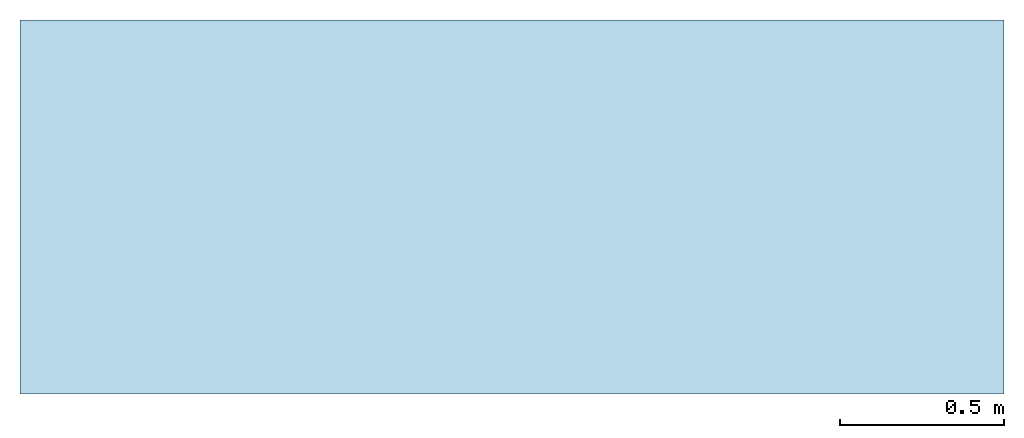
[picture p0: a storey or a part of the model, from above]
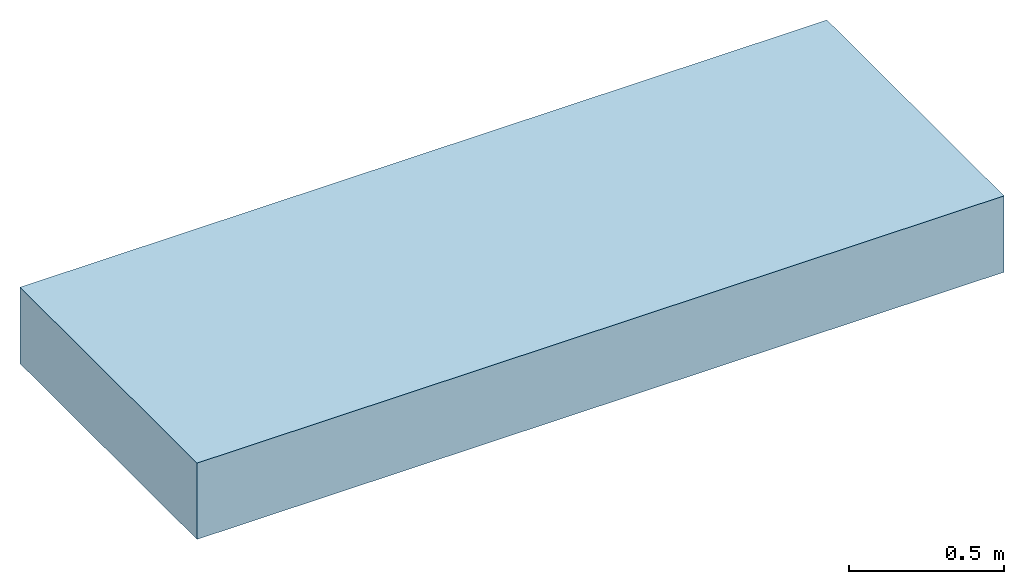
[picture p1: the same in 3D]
Properties of the parts of a building model (IFC2X3)

# File
Description: ViewDefinition [CoordinationView_V2.0, QuantityTakeOffAddOnView], RevitIdentifiers [ContentGUID: 704ee8e6-b7a5-4cdf-b516-c9cadaf13e75, VersionGUID: 389b4207-f0f3-4822-9464-d6dd4e263762, NumberOfSaves: 43], CoordinateReference [CoordinateBase: Shared Coordinates, ProjectSite: Internal]
File name: Solucion panel prefabricado ligero.ifc
Time: 2026-03-16T11:33:09+01:00
Written by: ODA SDAI 24.6
Made in: Autodesk Revit 24.3.40.26 (ESP) - IFC 24.3.20.0

# IfcProject, 000000
LongName: Solución panel prefabricado ligero de fachada

# IfcSite, Default
RefLatitude: 40, 25, 13, 9643; RefLongitude: -3, -42, -20, -772056; RefElevation: 0 m
Otra - Categoría: Información de proyecto; Dirección de proyecto: Parque Empresarial de A Pontenova , Parcelas 33-39 , 27720 · A Pontenova · (Lugo); Fecha de emisión de proyecto: 25-11-2025; Nombre de cliente: Recense; Nombre de proyecto: Solución panel prefabricado ligero de fachada; Número de proyecto: 000000
Datos de identidad - Autor: Deliprogal; Descripción de organización: Fijaciones a medida para prefabricado; Nombre de organización: Recense

# IfcBuilding
Pset_BuildingCommon - NumberOfStoreys: 3
Otra - Categoría: Información de proyecto; Dirección de proyecto: Parque Empresarial de A Pontenova , Parcelas 33-39 , 27720 · A Pontenova · (Lugo); Fecha de emisión de proyecto: 25-11-2025; Nombre de cliente: Recense; Nombre de proyecto: Solución panel prefabricado ligero de fachada; Número de proyecto: 000000
Datos de identidad - Autor: Deliprogal; Descripción de organización: Fijaciones a medida para prefabricado; Nombre de organización: Recense

# IfcBuildingStorey: Nivel:8mm Head (4)
Otra - Categoría: Niveles; Familia: Nivel; Familia y tipo: Nivel: 8mm Head; ID de tipo: 305; Tipo: 8mm Head
Cotas - Altura de cálculo: 0 m
Datos de identidad - Estructura: no; Planta de edificio: yes
Otra(Tipo) - Categoría: Niveles; Nombre de familia: Nivel
Restricciones(Tipo) - Base de elevación: Punto base del proyecto
Gráficos(Tipo) - Color: 12615680; Grosor de línea: 1; Patrón de línea: Dash dot; Símbolo en extremo 1 por defecto: no; Símbolo en extremo 2 por defecto: yes
Datos de identidad(Tipo) - Nombre de tipo: 8mm Head
Name | LongName = Nombre | Elevation (m) = Elevación (m)
B1 | B1 | -3
L0 | L0 | 0
L1 | L1 | 3
R1 | R1 | 6

# IfcBuildingElementProxy: Panel Hormigón:Panel Hormigón, Panel Hormigón:Panel Hormigón:3637775
In: B1
Type - Material: Hormigón reforzado con fibra de vidrio
Type - Otra - Categoría: Modelos genéricos; Nombre de familia: Panel Hormigón
Type - Restricciones - Elevación por defecto: 13.1234 m
Type - Datos de identidad - Nombre de tipo: Panel Hormigón
Pset_BuildingElementProxyCommon - Reference: Panel Hormigón; sets with these values: 2
Otra - Familia: Panel Hormigón; Familia y tipo: Panel Hormigón: Panel Hormigón; ID de tipo: 3674676; Tipo: Panel Hormigón
Restricciones - Desfase desde el anfitrión: -0.15 m; Elevación desde el nivel: 0 m; Plano de trabajo: <no asociado>
Cotas - Área: 9.7315 m2; Volumen: 1.0797 m3
Proceso por fases - Fase de creación: New

# IfcCovering: Techo compuesto:Aislamiento, Techo compuesto:Aislamiento:3635725
In: L0
Type - PredefinedType: CEILING
Type - Otra - Categoría: Techos; Nombre de familia: Techo compuesto
Type - Construcción - Grosor: 0.08 m
Type - Gráficos - Color de relleno de detalle bajo: 0
Type - Datos de identidad - Nombre de tipo: Aislamiento
Type - Propiedades analíticas - Absortancia: 0.7; Aspereza: 3; Coeficiente de transferencia de calor (U): 0.425 kg/K/s3; Masa térmica: 11360 kg/K/s2; Resistencia térmica (R): 2.35294 s3*K/kg
Type - Pset_CoveringCommon - TotalThickness: 0.08 m
Material: Lana de roca 0.08 m
Pset_CoveringCommon - Reference: Aislamiento; sets with these values: 2
BaseQuantities - GrossCeilingArea: 1.4356 m2
Otra - Familia: Techo compuesto; Familia y tipo: Techo compuesto: Aislamiento; ID de tipo: 3635518; Tipo: Aislamiento
Restricciones - Delimitación de habitación: yes; Nivel: L0; Desfase de altura desde nivel: 2.61 m
Cotas - Área: 1.4356 m2; Perímetro: 4.9 m; Volumen: 0.114848 m3
Proceso por fases - Fase de creación: New

# IfcCovering: Techo compuesto:Placa, Techo compuesto:Placa:3635732
In: L0
Type - PredefinedType: CEILING
Type - Otra - Categoría: Techos; Nombre de familia: Techo compuesto
Type - Construcción - Grosor: 0.01 m
Type - Gráficos - Color de relleno de detalle bajo: 0
Type - Datos de identidad - Nombre de tipo: Placa
Type - Propiedades analíticas - Absortancia: 0.7; Aspereza: 3; Coeficiente de transferencia de calor (U): 51 kg/K/s3; Masa térmica: 10752 kg/K/s2; Resistencia térmica (R): 0.0196078 s3*K/kg
Type - Pset_CoveringCommon - TotalThickness: 0.01 m
Material: Enlucido 0.01 m
Pset_CoveringCommon - Reference: Placa; Finish: Enlucido;
Pset_QuantityTakeOff - Reference: Placa
BaseQuantities - GrossCeilingArea: 1.2672 m2
Otra - Familia: Techo compuesto; Familia y tipo: Techo compuesto: Placa; ID de tipo: 3635581; Tipo: Placa
Restricciones - Delimitación de habitación: yes; Nivel: L0; Desfase de altura desde nivel: 2.6 m
Cotas - Área: 1.2672 m2; Perímetro: 4.56 m; Volumen: 0.012672 m3
Proceso por fases - Fase de creación: New

# IfcElementAssembly: GEN-A-M12:A-M12 (2)
In: L0
Type - Material: REC_Acero, S 275JR (Zincado)
Type - Otra - Categoría: Conexiones estructurales; Nombre de familia: GEN-A-M12
Type - Restricciones - Elevación por defecto: 0 m
Type - Datos - Classification.Uniclass.Pr.Description: Bolts and accessories; Classification.Uniclass.Pr.Number: Pr_20_29_08
Type - Datos de identidad - Código de montaje: Tornillo perfil hormigón M12x50 mm (8.8); Costo: 0; Creado por:: Deliprogal SL; Descripción: Arandela M12; Description_ESP: Concrete profile screw M12x50 mm (8.8); Fabricante: RECENSE; Fecha de Creacion:: 09/11/2025; Fecha Ultima Revision:: 12/02/2026; Keynote_ESP: Screw for fixing elements to the concrete profile PH4022; Modelo: TPH1250; Nombre de tipo: A-M12; Nota clave: Tornillo para fijar elementos al Perfil de Hormigón PH4022; URL: https://prefabricados.recense.com/prefabricados/fijacion/fijacion-antivuelco-hormigon/tph/
Classification: Tornillo perfil hormigón M12x50 mm (8.8) (Uniformat)
Pset_QuantityTakeOff - Reference: A-M12
Otra - Familia: GEN-A-M12; Familia y tipo: GEN-A-M12: A-M12; ID de tipo: 3651128; Tipo: A-M12
Restricciones - Se mueve con elementos cercanos: no; Anfitrión: Ninguno
Datos - DPG_FABRICA: IL; DPG_NUMERO_OT: OT-
Cotas - Área: 0.000441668 m2; Volumen: 7.16248e-07 m3
Proceso por fases - Fase de creación: New
Name (GEN-A-M12:A-M12:...)
3714486
3714490

# IfcElementAssembly: GEN-T-M12:T-M12 (2)
In: L0
Type - Material: REC_Acero, S 275JR (Zincado)
Type - Otra - Categoría: Conexiones estructurales; Nombre de familia: GEN-T-M12
Type - Restricciones - Elevación por defecto: 0 m
Type - Datos - Classification.Uniclass.Pr.Description: Bolts and accessories; Classification.Uniclass.Pr.Number: Pr_20_29_08
Type - Datos de identidad - Costo: 0; Creado por:: Deliprogal SL; Descripción: Concrete profile screw M12x50 mm (8.8); Description_ESP: Tornillo perfil hormigón M12x50 mm (8.8).; Fabricante: FERRETERÍA; Fecha de Creacion:: 01/03/2024; Fecha Ultima Revision:: 01/03/2024; Keynote_ESP: Screw for fixing elements to the concrete profile PH4022.; Modelo: TPH1250; Nombre de tipo: T-M12; Nota clave: Tornillo para fijar elementos al Perfil de Hormigón PH4022.; URL: https://prefabricados.recense.com/prefabricados/fijacion/fijacion-antivuelco-hormigon/tph/
Pset_QuantityTakeOff - Reference: T-M12
Otra - Familia: GEN-T-M12; Familia y tipo: GEN-T-M12: T-M12; ID de tipo: 3648613; Tipo: T-M12
Restricciones - Se mueve con elementos cercanos: no; Anfitrión: Ninguno
Cotas - Área: 0.000789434 m2; Volumen: 0.00000247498 m3
Proceso por fases - Fase de creación: New
Name (GEN-T-M12:T-M12:...)
3714487
3714491

# IfcElementAssembly: REC-A-M16:A-M16 (2)
In: L0
Type - Material: REC_Acero, S 275JR (Zincado)
Type - Otra - Categoría: Conexiones estructurales; Nombre de familia: REC-A-M16
Type - Restricciones - Elevación por defecto: 0 m
Type - Datos - Classification.Uniclass.Pr.Description: Bolts and accessories; Classification.Uniclass.Pr.Number: Pr_20_29_08
Type - Datos de identidad - Costo: 0; Creado por:: Deliprogal SL; Descripción: Arandela M16; Fabricante: RECENSE; Fecha de Creacion:: 01/03/2024; Fecha Ultima Revision:: 01/03/2024; Modelo: A-M16; Nombre de tipo: A-M16; URL: https://recense.com/
Pset_QuantityTakeOff - Reference: A-M16
Otra - Familia: REC-A-M16; Familia y tipo: REC-A-M16: A-M16; ID de tipo: 3811064; Tipo: A-M16
Restricciones - Se mueve con elementos cercanos: no; Anfitrión: Panel Hormigón : Panel Hormigón
Datos - DPG_FABRICA: IL; DPG_NUMERO_OT: OT-
Cotas - Área: 0.000701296 m2; Volumen: 0.00000143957 m3
Proceso por fases - Fase de creación: New
Name (REC-A-M16:A-M16:...)
3622922
3671388

# IfcElementAssembly: REC-AEM12-100:AEM12-100 (2)
In: L0
Type - Material: REC_Acero, S 275JR (Zincado)
Type - Otra - Categoría: Conexiones estructurales; Nombre de familia: REC-AEM12-100
Type - Restricciones - Elevación por defecto: 0 m
Type - Datos - Classification.Uniclass.Pr.Description: Bolts and accessories; Classification.Uniclass.Pr.Number: Pr_20_29_08
Type - Datos de identidad - Costo: 0; Creado por:: Deliprogal SL; Descripción: Anclaje M12; Fabricante: RECENSE; Fecha de Creacion:: 01/03/2024; Fecha Ultima Revision:: 16/03/2026; Modelo: AEM12-100; Nombre de tipo: AEM12-100; URL: https://recense.com/
Pset_QuantityTakeOff - Reference: AEM12-100
Otra - Familia: REC-AEM12-100; Familia y tipo: REC-AEM12-100: AEM12-100; ID de tipo: 3817933; Tipo: AEM12-100
Restricciones - Se mueve con elementos cercanos: no; Anfitrión: Ninguno
Datos - DPG_FABRICA: IL; DPG_NUMERO_OT: OT-
Cotas - Área: 0.00338965 m2; Volumen: 0.0000142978 m3
Proceso por fases - Fase de creación: New
Name (REC-AEM12-100:AEM12-100:...)
3693162
3693229

# IfcElementAssembly: REC-AEM12-140:AEM12-140 (2)
In: B1
Type - Material: REC_Acero, S 275JR (Zincado)
Type - Otra - Categoría: Conexiones estructurales; Nombre de familia: REC-AEM12-140
Type - Restricciones - Elevación por defecto: 0 m
Type - Datos - Classification.Uniclass.Pr.Description: Bolts and accessories; Classification.Uniclass.Pr.Number: Pr_20_29_08
Type - Datos de identidad - Costo: 0; Creado por:: Deliprogal SL; Descripción: Anclaje M12; Fabricante: RECENSE; Fecha de Creacion:: 07/11/2025; Fecha Ultima Revision:: 16/03/2026; Modelo: AEM12-140; Nombre de tipo: AEM12-140; URL: https://recense.com/
Pset_QuantityTakeOff - Reference: AEM12-140
Otra - Familia: REC-AEM12-140; Familia y tipo: REC-AEM12-140: AEM12-140; ID de tipo: 3811065; Tipo: AEM12-140
Restricciones - Se mueve con elementos cercanos: no; Anfitrión: Panel Hormigón : Panel Hormigón
Cotas - Área: 0.00414363 m2; Volumen: 0.0000188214 m3
Proceso por fases - Fase de creación: New
Name (REC-AEM12-140:AEM12-140:...)
3622924
3671390

# IfcElementAssembly: REC-CPA448T17:CPA448T17 (2)
In: L0
Type - Material: REC_Acero, S 275JR (Zincado)
Type - Otra - Categoría: Conexiones estructurales; Nombre de familia: REC-CPA448T17
Type - Restricciones - Elevación por defecto: 0 m
Type - Datos - Classification.Uniclass.Pr.Description: Plate (square) washers; Classification.Uniclass.Pr.Number: Pr_20_29_60_63
Type - Datos de identidad - Costo: 0; Creado por:: Deliprogal SL; Descripción: Contraplaca antideslizante; Fabricante: RECENSE; Fecha de Creacion:: 10/11/2025; Fecha Ultima Revision:: 16/03/2026; Modelo: CPA448T17; Nombre de tipo: CPA448T17; URL: https://prefabricados.recense.com/prefabricados/fijacion/fijacion-antivuelco-hormigon/para2501208rt/
Pset_QuantityTakeOff - Reference: CPA448T17
Otra - Familia: REC-CPA448T17; Familia y tipo: REC-CPA448T17: CPA448T17; ID de tipo: 3606529; Tipo: CPA448T17
Restricciones - Se mueve con elementos cercanos: no; Anfitrión: Ninguno
Datos - DPG_FABRICA: IL; DPG_NUMERO_OT: OT-
Cotas - Área: 0.00433573 m2; Volumen: 0.0000136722 m3
Proceso por fases - Fase de creación: New
Name (REC-CPA448T17:CPA448T17:...)
3792154
3792157

# IfcElementAssembly: REC-HBP M16-75 EV:HBP M16-75 EV (2)
In: L0
Type - Material: REC_Acero, S 275JR (Zincado)
Type - Otra - Categoría: Conexiones estructurales; Nombre de familia: REC-HBP M16-75 EV
Type - Restricciones - Elevación por defecto: 0 m
Type - Datos - Classification.Uniclass.Pr.Description: Lifting anchors; Classification.Uniclass.Pr.Number: Pr_20_29_03_47
Type - Datos de identidad - Costo: 0; Creado por:: Deliprogal SL; Descripción: Casquillo fijación HBP; Description_ESP: CASQUILLO; Fabricante: RECENSE; Fecha de Creacion:: 07/11/2025; Fecha Ultima Revision:: 06/02/2026; Keynote_ESP: Casquillo e insertos roscados hembra para dejar embebidos en los prefabricados de hormigón y ser usados posteriormente para su fijación a la estructura del edificio, o para la instalación de elementos auxiliares.; Modelo: HBP M16x75 EV; Nombre de tipo: HBP M16-75 EV; Nota clave: Female threaded sleeves and inserts designed to be embedded in precast concrete elements and later used for fastening them to the building structure or for installing auxiliary components.; URL: https://prefabricados.recense.com/prefabricados/fijacion/casquillos-estandar/
Pset_QuantityTakeOff - Reference: HBP M16-75 EV
Otra - Familia: REC-HBP M16-75 EV; Familia y tipo: REC-HBP M16-75 EV: HBP M16-75 EV; ID de tipo: 3606532; Tipo: HBP M16-75 EV
Restricciones - Anfitrión: Panel Hormigón : Panel Hormigón; Se mueve con elementos cercanos: no
Cotas - Área: 0.00790422 m2; Volumen: 0.0000329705 m3
Proceso por fases - Fase de creación: New
Estructura - Recubrimiento de armadura: Rebar Cover 1 <25 mm>
Name (REC-HBP M16-75 EV:HBP M16-75 EV:...)
3622921
3671387

# IfcElementAssembly: REC-M16-45:M16-45 (2)
In: L0
Type - Material: REC_Acero, S 275JR (Zincado)
Type - Otra - Categoría: Conexiones estructurales; Nombre de familia: REC-M16-45
Type - Restricciones - Elevación por defecto: 0 m
Type - Datos - Classification.Uniclass.Pr.Description: Bolts and accessories; Classification.Uniclass.Pr.Number: Pr_20_29_08
Type - Datos de identidad - Costo: 0; Creado por:: Deliprogal SL; Descripción: Tornillo M16 L=45; Fabricante: RECENSE; Fecha de Creacion:: 01/03/2024; Fecha Ultima Revision:: 01/03/2024; Modelo: M16-45; Nombre de tipo: M16-45; URL: https://recense.com/
Pset_QuantityTakeOff - Reference: M16-45
Otra - Familia: REC-M16-45; Familia y tipo: REC-M16-45: M16-45; ID de tipo: 3811063; Tipo: M16-45
Restricciones - Se mueve con elementos cercanos: no; Anfitrión: Panel Hormigón : Panel Hormigón
Datos - DPG_FABRICA: IL; DPG_NUMERO_OT: OT-
Cotas - Área: 0.00240261 m2; Volumen: 0.0000157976 m3
Proceso por fases - Fase de creación: New
Name (REC-M16-45:M16-45:...)
3622923
3671389

# IfcElementAssembly: REC-PAA150708T14:PAA150708T14 (2)
In: L0
Type - Material: REC_Acero, S 275JR (Zincado)
Type - Otra - Categoría: Conexiones estructurales; Nombre de familia: REC-PAA150708T14
Type - Restricciones - Elevación por defecto: 0 m
Type - Datos - Classification.Uniclass.Pr.Description: Carbon steel anchor plates; Classification.Uniclass.Pr.Number: Pr_20_29_03_10
Type - Datos de identidad - Costo: 0; Creado por:: Deliprogal SL; Descripción: Non-slip angle plate 150x70x50x8, with 3 holes Ø14 mm on one side and hole Ø14 mm on another side.; Description_ESP: Pletina angular antideslizante 150x70x50x8 mm, 3 taladros TØ14 mm en un ala y TØ14 mm en la otra.; Fabricante: RECENSE; Fecha de Creacion:: 01/11/2025; Fecha Ultima Revision:: 06/02/2025; Keynote_ESP: Anclaje antivuelco para fijación de paneles a estructura de hormigón mediante la interposición de perfiles y/ó tornillos de anclaje expansivo.; Modelo: PAA150708T14; Nombre de tipo: PAA150708T14; Nota clave: Anti-tilt anchor for fixing panels to concrete structures by means of interposing profiles and/or expansion anchor bolts.; URL: https://prefabricados.recense.com/prefabricados/fijacion/fijacion-antivuelco-hormigon/paaxxx708t14/
Type - Visibilidad - Visible: yes
Pset_QuantityTakeOff - Reference: PAA150708T14
Otra - Familia: REC-PAA150708T14; Familia y tipo: REC-PAA150708T14: PAA150708T14; ID de tipo: 3746429; Tipo: PAA150708T14
Restricciones - Se mueve con elementos cercanos: no; Anfitrión: Ninguno
Cotas - Área: 0.0125823 m2; Volumen: 0.0000784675 m3
Proceso por fases - Fase de creación: New
Name (REC-PAA150708T14:PAA150708T14:...)
3746638
3746640

# IfcElementAssembly: REC-PARA2501208RT:PARA2501208RT (2)
In: L0
Type - Material: REC_Acero, S 275JR (Zincado)
Type - Otra - Categoría: Conexiones estructurales; Nombre de familia: REC-PARA2501208RT
Type - Restricciones - Elevación por defecto: 0 m
Type - Datos - Classification.Uniclass.Pr.Description: Brackets; Classification.Uniclass.Pr.Number: Pr_20_85_09
Type - Datos de identidad - Costo: 0; Creado por:: Deliprogal SL; Descripción: Pletina reforzada PARA; Fabricante: RECENSE; Fecha de Creacion:: 8/11/2025; Fecha Ultima Revision:: 16/03/2026; Modelo: PARA2501208RT; Nombre de tipo: PARA2501208RT; URL: https://prefabricados.recense.com/prefabricados/fijacion/fijacion-antivuelco-hormigon/para2501208rt/
Pset_QuantityTakeOff - Reference: PARA2501208RT
Otra - Familia: REC-PARA2501208RT; Familia y tipo: REC-PARA2501208RT: PARA2501208RT; ID de tipo: 3606530; Tipo: PARA2501208RT
Restricciones - Se mueve con elementos cercanos: no; Anfitrión: Ninguno
Cotas - Área: 0.0616333 m2; Volumen: 0.000369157 m3
Proceso por fases - Fase de creación: New
Name (REC-PARA2501208RT:PARA2501208RT:...)
3792153
3792156

# IfcElementAssembly: REC-PH4022:PH4022 (2)
In: L0
Type - Material: REC_Acero, S 275JR (Zincado)
Type - Otra - Categoría: Conexiones estructurales; Nombre de familia: REC-PH4022
Type - Restricciones - Elevación por defecto: 0 m
Type - Datos - Classification.Uniclass.Pr.Description: Carbon steel cast-in channels; Classification.Uniclass.Pr.Number: Pr_20_85_84_11
Type - Datos de identidad - Costo: 0; Creado por:: Deliprogal SL; Descripción: Concrete profile 150x67x40x22x22x2.5 mm.; Description_ESP: Perfil hormigón 150x67x40x22x2.5 mm.; Fabricante: RECENSE; Fecha de Creacion:: 10/11/2025; Fecha Ultima Revision:: 06/02/2026; Keynote_ESP: Perfil para dejar embebido en elementos de hormigón para su posterior fijación mediante Tornillos de Perfil de Hormigón TPH y el anclaje correspondiente.; Modelo: PH4022; Nombre de tipo: PH4022; Nota clave: Profile to be embedded in concrete elements for subsequent fixing by means of TPH Concrete Profile Screws and the corresponding anchorage.; URL: https://prefabricados.recense.com/prefabricados/fijacion/fijacion-antivuelco-hormigon/ph4022/
Pset_QuantityTakeOff - Reference: PH4022
Otra - Familia: REC-PH4022; Familia y tipo: REC-PH4022: PH4022; ID de tipo: 3740374; Tipo: PH4022
Restricciones - Se mueve con elementos cercanos: no; Anfitrión: Ninguno
Cotas - Área: 0.016689 m2; Volumen: 0.0000420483 m3
Proceso por fases - Fase de creación: New
Name (REC-PH4022:PH4022:...)
3708163
3708165

# IfcElementAssembly: REC-TPH1250:TPH1250 (2)
In: L0
Type - Material: REC_Acero, S 275JR (Zincado)
Type - Otra - Categoría: Conexiones estructurales; Nombre de familia: REC-TPH1250
Type - Restricciones - Elevación por defecto: 0 m
Type - Datos - Classification.Uniclass.Pr.Description: Bolts and accessories; Classification.Uniclass.Pr.Number: Pr_20_29_08
Type - Datos de identidad - Costo: 0; Creado por:: Deliprogal SL; Descripción: Concrete profile screw M12x50 mm (8.8); Description_ESP: Tornillo perfil hormigón M12x50 mm (8.8).; Fabricante: RECENSE; Fecha de Creacion:: 9/11/2025; Fecha Ultima Revision:: 06/02/2026; Keynote_ESP: Tornillo para fijar elementos al Perfil de Hormigón PH4022.; Modelo: TPH1250; Nombre de tipo: TPH1250; Nota clave: Screw for fixing elements to the concrete profile PH4022.; URL: https://prefabricados.recense.com/prefabricados/fijacion/fijacion-antivuelco-hormigon/tph/
Pset_QuantityTakeOff - Reference: TPH1250
Otra - Familia: REC-TPH1250; Familia y tipo: REC-TPH1250: TPH1250; ID de tipo: 3566361; Tipo: TPH1250
Restricciones - Se mueve con elementos cercanos: no; Anfitrión: Ninguno
Cotas - Área: 0.00199136 m2; DPG_PosicionTuerca: 0.015 m; Volumen: 0.00000937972 m3
Proceso por fases - Fase de creación: New
Name (REC-TPH1250:TPH1250:...)
3693161
3693228

# IfcOpeningElement: Opening (8)
In: L0
BaseQuantities - Depth: 0.05 m; Area: 0.00166786 m2
Pset_OpeningElementCommon - Reference: PAA150708T14; sets with these values: 2
Name (REC-PAA150708T14:PAA150708T14:...)
3746638:1
3746638:2
3746638:3
3746638:4
3746640:1
3746640:2
3746640:3
3746640:4

# IfcSlab: Suelo:DPG_Aislamiento Suelo, Suelo:DPG_Aislamiento Suelo:3607158
In: L0
Type - PredefinedType: FLOOR; Material: Lana de roca 0.04 m
Type - Otra - Categoría: Suelos; Nombre de familia: Suelo
Type - Construcción - Función: Interior; Grosor predeterminado: 0.04 m
Type - Gráficos - Color de relleno de detalle bajo: 0
Type - Datos de identidad - Nombre de tipo: DPG_Aislamiento Suelo
Type - Materiales y acabados - Material estructural: Lana de roca
Type - Propiedades analíticas - Absortancia: 0.7; Aspereza: 3; Coeficiente de transferencia de calor (U): 0.85 kg/K/s3; Masa térmica: 5680 kg/K/s2; Resistencia térmica (R): 1.17647 s3*K/kg
Type - Pset_SlabCommon - ThermalTransmittance: 0.85 kg/K/s3
Pset_QuantityTakeOff - Reference: DPG_Aislamiento Suelo; sets with these values: 2
Pset_SlabCommon - IsExternal: no; LoadBearing: no; PitchAngle: 0 deg; Reference: DPG_Aislamiento Suelo
BaseQuantities - Width: 1.64 m; Perimeter: 5.22 m; GrossArea: 1.5908 m2; NetArea: 1.5908 m2; GrossVolume: 0.063632 m3; NetVolume: 0.063632 m3
Otra - Familia: Suelo; Familia y tipo: Suelo: DPG_Aislamiento Suelo; ID de tipo: 3607200; Tipo: DPG_Aislamiento Suelo
Restricciones - Delimitación de habitación: yes; Nivel: L0; Relacionado con masa: no; Desfase de altura desde nivel: 0.04 m
Cotas - Área: 1.5908 m2; Elevación en parte inferior: 0 m; Elevación en parte inferior de núcleo: 0 m; Elevación en parte superior: 0.04 m; Elevación en parte superior de núcleo: 0.04 m; Grosor: 0.04 m; Perímetro: 5.22 m; Volumen: 0.063632 m3
Datos de identidad - Tiene asociación: no
Proceso por fases - Fase de creación: New
Estructura - Estructura: no

# IfcSlab: Suelo:DPG_Ceramica, Suelo:DPG_Ceramica:3607525
In: L0
Type - PredefinedType: FLOOR; Material: Azulejo, porcelana, 6 pulg. 0.01 m
Type - Otra - Categoría: Suelos; Nombre de familia: Suelo
Type - Construcción - Función: Interior; Grosor predeterminado: 0.01 m
Type - Gráficos - Color de relleno de detalle bajo: 0
Type - Datos de identidad - Nombre de tipo: DPG_Ceramica
Type - Materiales y acabados - Material estructural: Azulejo, porcelana, 6 pulg.
Type - Propiedades analíticas - Absortancia: 0.7; Aspereza: 3; Coeficiente de transferencia de calor (U): 120 kg/K/s3; Masa térmica: 17000 kg/K/s2; Resistencia térmica (R): 0.00833333 s3*K/kg
Type - Pset_SlabCommon - ThermalTransmittance: 120 kg/K/s3
Pset_QuantityTakeOff - Reference: DPG_Ceramica; sets with these values: 2
Pset_SlabCommon - IsExternal: no; LoadBearing: no; PitchAngle: 0 deg; Reference: DPG_Ceramica
BaseQuantities - Width: 1.32 m; Perimeter: 4.58 m; GrossArea: 1.2804 m2; NetArea: 1.2804 m2; GrossVolume: 0.012804 m3; NetVolume: 0.012804 m3
Otra - Familia: Suelo; Familia y tipo: Suelo: DPG_Ceramica; ID de tipo: 3607552; Tipo: DPG_Ceramica
Restricciones - Delimitación de habitación: yes; Nivel: L0; Relacionado con masa: no; Desfase de altura desde nivel: 0.11 m
Cotas - Área: 1.2804 m2; Elevación en parte inferior: 0.1 m; Elevación en parte inferior de núcleo: 0.1 m; Elevación en parte superior: 0.11 m; Elevación en parte superior de núcleo: 0.11 m; Grosor: 0.01 m; Perímetro: 4.58 m; Volumen: 0.012804 m3
Datos de identidad - Tiene asociación: no
Proceso por fases - Fase de creación: New
Estructura - Estructura: no

# IfcSlab: Suelo:DPG_Losa Principal Obra (2)
Type - PredefinedType: FLOOR; Material: DPG_Losa Principal Obra 0.3 m
Type - Otra - Categoría: Suelos; Nombre de familia: Suelo
Type - Construcción - Función: Interior; Grosor predeterminado: 0.3 m
Type - Gráficos - Color de relleno de detalle bajo: 0
Type - Datos de identidad - Nombre de tipo: DPG_Losa Principal Obra
Type - Materiales y acabados - Material estructural: DPG_Losa Principal Obra
Type - Propiedades analíticas - Absortancia: 0.7; Aspereza: 3
Pset_QuantityTakeOff - Reference: DPG_Losa Principal Obra; sets with these values: 2
Pset_SlabCommon - Reference: DPG_Losa Principal Obra; IsExternal: no; LoadBearing: no; PitchAngle: 0 deg
BaseQuantities - Width: 3 m; Perimeter: 8.28 m; GrossArea: 3.42 m2; NetArea: 3.42 m2; GrossVolume: 1.026 m3; NetVolume: 1.026 m3
Otra - Familia: Suelo; Familia y tipo: Suelo: DPG_Losa Principal Obra; ID de tipo: 759; Tipo: DPG_Losa Principal Obra
Restricciones - Delimitación de habitación: yes; Relacionado con masa: no
Cotas - Área: 3.42 m2; Grosor: 0.3 m; Perímetro: 8.28 m; Volumen: 1.026 m3
Datos de identidad - Tiene asociación: no
Proceso por fases - Fase de creación: New
Estructura - Estructura: no
Name (Suelo:DPG_Losa Principal Obra:...) | In | Desfase de altura desde nivel (m) | Nivel | Elevación en parte inferior (m) = Elevación en parte inferior de núcleo (m) | Elevación en parte superior (m) = Elevación en parte superior de núcleo (m)
3592091 | L0 | 0 | L0 | -0.3 | 0
3645118 | L1 | 0.02 | L1 | 2.72 | 3.02

# IfcSlab: Suelo:DPG_Pegamento cemento, Suelo:DPG_Pegamento cemento:3607421
In: L0
Type - PredefinedType: FLOOR; Material: Hormigón - Hormigón moldeado in situ 0.01 m
Type - Otra - Categoría: Suelos; Nombre de familia: Suelo
Type - Construcción - Función: Interior; Grosor predeterminado: 0.01 m
Type - Gráficos - Color de relleno de detalle bajo: 0
Type - Datos de identidad - Nombre de tipo: DPG_Pegamento cemento
Type - Materiales y acabados - Material estructural: Hormigón - Hormigón moldeado in situ
Type - Propiedades analíticas - Absortancia: 0.7; Aspereza: 3
Pset_QuantityTakeOff - Reference: DPG_Pegamento cemento; sets with these values: 2
Pset_SlabCommon - IsExternal: no; LoadBearing: no; PitchAngle: 0 deg; Reference: DPG_Pegamento cemento
BaseQuantities - Width: 1.44 m; Perimeter: 4.82 m; GrossArea: 1.3968 m2; NetArea: 1.3968 m2; GrossVolume: 0.013968 m3; NetVolume: 0.013968 m3
Otra - Familia: Suelo; Familia y tipo: Suelo: DPG_Pegamento cemento; ID de tipo: 3607442; Tipo: DPG_Pegamento cemento
Restricciones - Delimitación de habitación: yes; Nivel: L0; Relacionado con masa: no; Desfase de altura desde nivel: 0.1 m
Cotas - Área: 1.3968 m2; Elevación en parte inferior: 0.09 m; Elevación en parte inferior de núcleo: 0.09 m; Elevación en parte superior: 0.1 m; Elevación en parte superior de núcleo: 0.1 m; Grosor: 0.01 m; Perímetro: 4.82 m; Volumen: 0.013968 m3
Datos de identidad - Tiene asociación: no
Proceso por fases - Fase de creación: New
Estructura - Estructura: no

# IfcSlab: Suelo:DPG_Recrecido, Suelo:DPG_Recrecido:3607293
In: L0
Type - PredefinedType: FLOOR; Material: Hormigón, ligero 0.05 m
Type - Otra - Categoría: Suelos; Nombre de familia: Suelo
Type - Construcción - Función: Interior; Grosor predeterminado: 0.05 m
Type - Gráficos - Color de relleno de detalle bajo: 0
Type - Datos de identidad - Nombre de tipo: DPG_Recrecido
Type - Materiales y acabados - Material estructural: Hormigón, ligero
Type - Propiedades analíticas - Absortancia: 0.7; Aspereza: 3; Coeficiente de transferencia de calor (U): 4.18 kg/K/s3; Masa térmica: 31207.5 kg/K/s2; Resistencia térmica (R): 0.239234 s3*K/kg
Type - Pset_SlabCommon - ThermalTransmittance: 4.18 kg/K/s3
Pset_QuantityTakeOff - Reference: DPG_Recrecido; sets with these values: 2
Pset_SlabCommon - IsExternal: no; LoadBearing: no; PitchAngle: 0 deg; Reference: DPG_Recrecido
BaseQuantities - Width: 1.54 m; Perimeter: 5.02 m; GrossArea: 1.4938 m2; NetArea: 1.4938 m2; GrossVolume: 0.07469 m3; NetVolume: 0.07469 m3
Otra - Familia: Suelo; Familia y tipo: Suelo: DPG_Recrecido; ID de tipo: 3607308; Tipo: DPG_Recrecido
Restricciones - Delimitación de habitación: yes; Nivel: L0; Relacionado con masa: no; Desfase de altura desde nivel: 0.09 m
Cotas - Área: 1.4938 m2; Elevación en parte inferior: 0.04 m; Elevación en parte inferior de núcleo: 0.04 m; Elevación en parte superior: 0.09 m; Elevación en parte superior de núcleo: 0.09 m; Grosor: 0.05 m; Perímetro: 5.02 m; Volumen: 0.07469 m3
Datos de identidad - Tiene asociación: no
Proceso por fases - Fase de creación: New
Estructura - Estructura: no

# IfcWallStandardCase: Muro básico:DPG_Aislamiento, Muro básico:DPG_Aislamiento:3607087
In: L0
Type - PredefinedType: STANDARD; Material: Lana de roca 0.1 m
Type - Otra - Categoría: Muros; Nombre de familia: Muro básico
Type - Construcción - Anchura: 0.1 m; Envolvente en extremos: Ninguno; Envolvente en inserciones: Sin envolvente; Función: Retención
Type - Gráficos - Color de relleno de detalle bajo: 0
Type - Datos de identidad - Nombre de tipo: DPG_Aislamiento
Type - Propiedades analíticas - Absortancia: 0.7; Aspereza: 3; Coeficiente de transferencia de calor (U): 0.34 kg/K/s3; Masa térmica: 14200 kg/K/s2; Resistencia térmica (R): 2.94118 s3*K/kg
Type - Pset_WallCommon - ThermalTransmittance: 0.34 kg/K/s3
BaseQuantities - Height: 2.72 m; Length: 1.76 m; Width: 0.1 m; GrossFootprintArea: 0.176 m2; GrossVolume: 0.47872 m3; GrossSideArea: 4.7872 m2; NetSideArea: 4.7872 m2; NetVolume: 0.47872 m3
Pset_QuantityTakeOff - Reference: DPG_Aislamiento; sets with these values: 2
Pset_WallCommon - LoadBearing: no; Reference: DPG_Aislamiento; IsExternal: yes; ExtendToStructure: no
Otra - Familia: Muro básico; Familia y tipo: Muro básico: DPG_Aislamiento; ID de tipo: 3607102; Tipo: DPG_Aislamiento
Restricciones - Relacionado con masa: no; Altura desconectada: 2.72 m; Delimitación de habitación: no; Desfase de base: 0 m; Desfase superior: 0 m; Distancia de extensión de base: 0 m; Distancia de extensión superior: 0 m; La base está enlazada: no; La parte superior está enlazada: no; Línea de ubicación: Cara de acabado: Exterior; Restricción de base: L0
Cotas - Área: 4.7872 m2; Longitud: 1.76 m; Volumen: 0.47872 m3
Proceso por fases - Fase de creación: New
Estructura - Estructura: no; Uso estructural: No portante
Definición de sección transversal - Sección transversal: Vertical

# IfcWallStandardCase: Muro básico:DPG_Enlucido, Muro básico:DPG_Enlucido:3608548
In: L0
Type - PredefinedType: STANDARD; Material: Enlucido 0.01 m
Type - Otra - Categoría: Muros; Nombre de familia: Muro básico
Type - Construcción - Envolvente en extremos: Ninguno; Envolvente en inserciones: Sin envolvente; Función: Retención; Anchura: 0.01 m
Type - Gráficos - Color de relleno de detalle bajo: 0
Type - Datos de identidad - Nombre de tipo: DPG_Enlucido
Type - Propiedades analíticas - Absortancia: 0.7; Aspereza: 3; Coeficiente de transferencia de calor (U): 51 kg/K/s3; Masa térmica: 10752 kg/K/s2; Resistencia térmica (R): 0.0196078 s3*K/kg
Type - Pset_WallCommon - ThermalTransmittance: 51 kg/K/s3
BaseQuantities - Height: 2.5 m; Length: 1.32 m; Width: 0.01 m; GrossFootprintArea: 0.0132 m2; GrossVolume: 0.033 m3; GrossSideArea: 3.3 m2; NetSideArea: 3.3 m2; NetVolume: 0.033 m3
Pset_QuantityTakeOff - Reference: DPG_Enlucido; sets with these values: 2
Pset_WallCommon - LoadBearing: no; IsExternal: yes; ExtendToStructure: no; Reference: DPG_Enlucido
Otra - Familia: Muro básico; Familia y tipo: Muro básico: DPG_Enlucido; ID de tipo: 3608303; Tipo: DPG_Enlucido
Restricciones - Relacionado con masa: no; Delimitación de habitación: no; Desfase superior: 0 m; Distancia de extensión de base: 0 m; Distancia de extensión superior: 0 m; La base está enlazada: no; La parte superior está enlazada: no; Línea de ubicación: Cara de acabado: Exterior; Restricción de base: L0; Altura desconectada: 2.5 m; Desfase de base: 0.11 m
Cotas - Área: 3.3 m2; Longitud: 1.32 m; Volumen: 0.033 m3
Proceso por fases - Fase de creación: New
Estructura - Estructura: no; Uso estructural: No portante
Definición de sección transversal - Sección transversal: Vertical

# IfcWallStandardCase: Muro básico:DPG_Ladrillo, Muro básico:DPG_Ladrillo:3607614
In: L0
Type - PredefinedType: STANDARD; Material: Ladrillo, común, marrón 0.07 m
Type - Otra - Categoría: Muros; Nombre de familia: Muro básico
Type - Construcción - Envolvente en extremos: Ninguno; Envolvente en inserciones: Sin envolvente; Función: Retención; Anchura: 0.07 m
Type - Gráficos - Color de relleno de detalle bajo: 0
Type - Datos de identidad - Nombre de tipo: DPG_Ladrillo
Type - Propiedades analíticas - Absortancia: 0.7; Aspereza: 3; Coeficiente de transferencia de calor (U): 7.71429 kg/K/s3; Masa térmica: 91140 kg/K/s2; Resistencia térmica (R): 0.12963 s3*K/kg
Type - Pset_WallCommon - ThermalTransmittance: 7.71429 kg/K/s3
BaseQuantities - Height: 2.72 m; Length: 1.64 m; Width: 0.07 m; GrossFootprintArea: 0.1148 m2; GrossVolume: 0.312256 m3; GrossSideArea: 4.4608 m2; NetSideArea: 4.4608 m2; NetVolume: 0.312256 m3
Pset_QuantityTakeOff - Reference: DPG_Ladrillo; sets with these values: 2
Pset_WallCommon - LoadBearing: no; IsExternal: yes; ExtendToStructure: no; Reference: DPG_Ladrillo
Otra - Familia: Muro básico; Familia y tipo: Muro básico: DPG_Ladrillo; ID de tipo: 3607732; Tipo: DPG_Ladrillo
Restricciones - Relacionado con masa: no; Delimitación de habitación: no; Desfase de base: 0 m; Desfase superior: 0 m; Distancia de extensión de base: 0 m; Distancia de extensión superior: 0 m; La base está enlazada: no; La parte superior está enlazada: no; Línea de ubicación: Cara de acabado: Exterior; Restricción de base: L0; Altura desconectada: 2.72 m
Cotas - Área: 4.4608 m2; Longitud: 1.64 m; Volumen: 0.312256 m3
Proceso por fases - Fase de creación: New
Estructura - Estructura: no; Uso estructural: No portante
Definición de sección transversal - Sección transversal: Vertical
